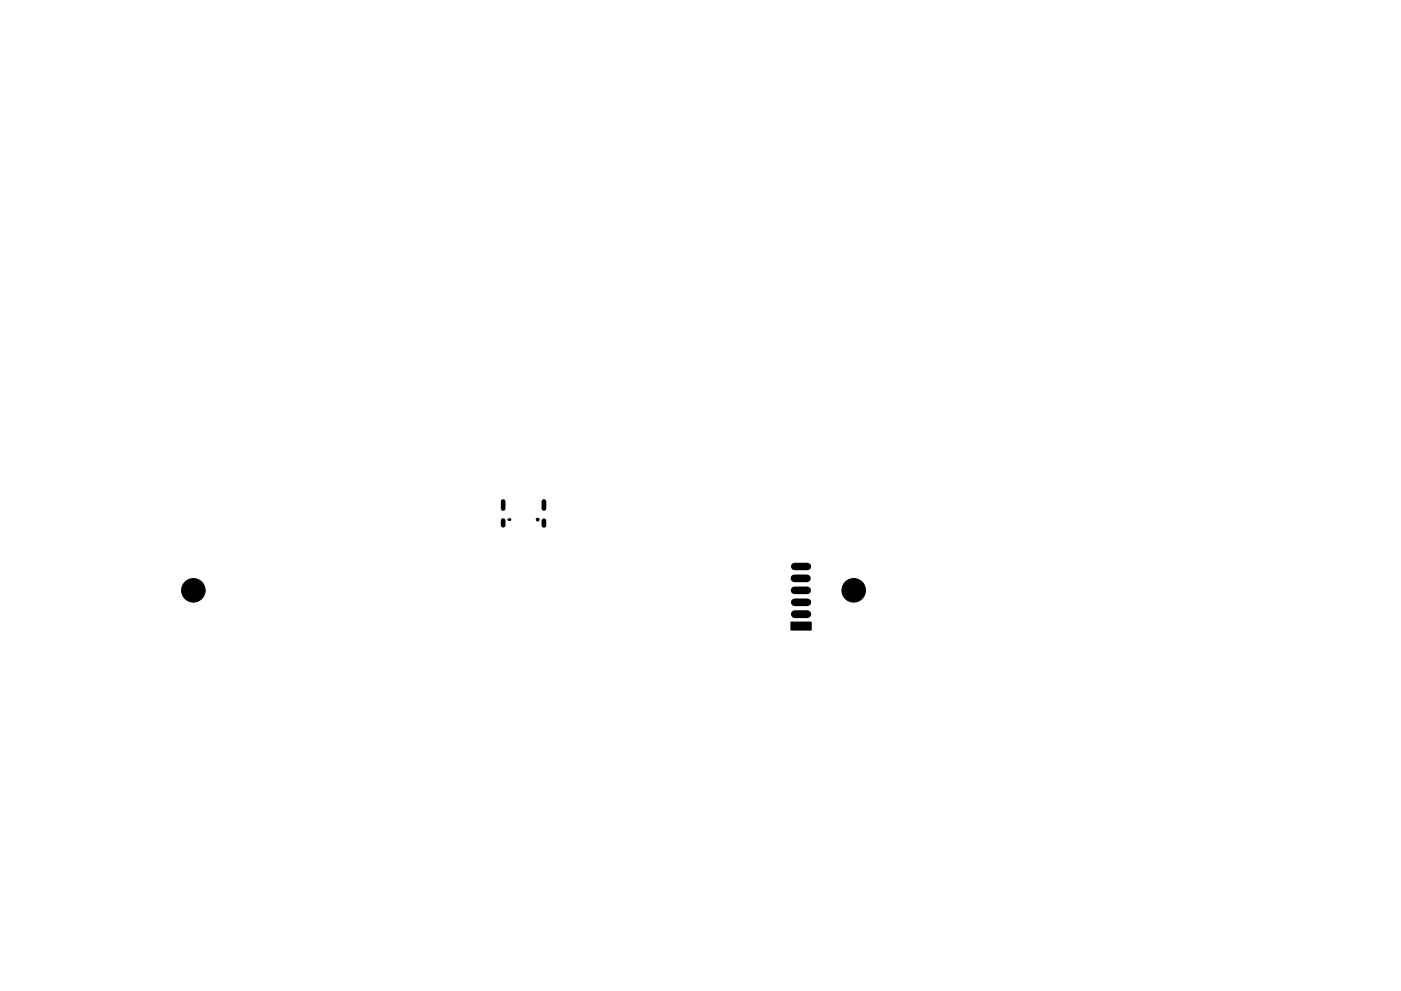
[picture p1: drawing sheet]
<svg xmlns="http://www.w3.org/2000/svg" width="297mm" height="210mm" viewBox="0 0 297 210" stroke-linecap="round" stroke-linejoin="round" font-family="sans-serif">
<g fill="#000" stroke="#000" stroke-width=".21">
<path d="M167.7 132h4.3v1.7h-4.3z"/>
<circle cx="114" cy="110.2" r=".3"/>
<circle cx="41" cy="125.2" r="2.5"/>
<circle cx="181" cy="125.2" r="2.5"/>
</g>
<path d="M168.5 130.3h2.7" fill="none" stroke="#000" stroke-width="1.7"/>
<path d="M168.4 122.7h2.7M168.5 125.2h2.6M168.5 120.2h2.7M168.5 127.8h2.7" fill="none" stroke="#000" stroke-width="1.6"/>
<path d="M106.7 106.4v1.5M106.7 110.4v1M115.3 106.4v1.5M115.3 110.5v1" fill="none" stroke="#000" stroke-width="1"/>
<path d="M107.9 110.2h.2" fill="none" stroke="#000" stroke-width=".6"/>
</svg>
